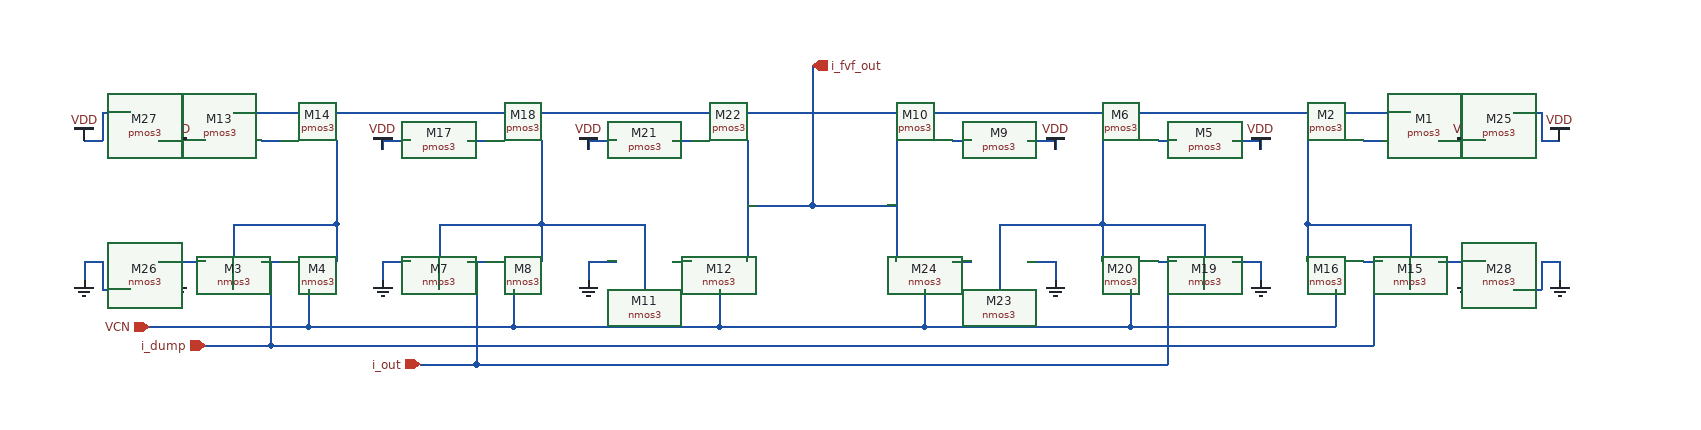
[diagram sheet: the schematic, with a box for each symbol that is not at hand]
v {xschem version=3.4.3 file_version=1.2
}
G {}
K {}
V {}
S {}
E {}
N 770 -210 790 -210 {
lab=#net1}
N -330 -210 -330 -120 {
lab=#net3}
N -410 -80 -390 -80 {
lab=i_dump}
N -440 -120 -330 -120 {
lab=#net3}
N -440 -120 -440 -50 {
lab=#net3}
N -330 -120 -330 -80 {
lab=#net3}
N -360 -50 -360 -10 {
lab=VCN}
N -500 -10 -360 -10 {
lab=VCN}
N -500 -80 -470 -80 {
lab=GND}
N -500 -80 -500 -60 {
lab=GND}
N 880 -210 880 -200 {
lab=VDD}
N 850 -210 880 -210 {
lab=VDD}
N -530 -10 -500 -10 {
lab=VCN}
N 550 -210 570 -210 {
lab=#net4}
N -110 -210 -110 -120 {
lab=#net6}
N -190 -80 -170 -80 {
lab=i_dump}
N -220 -120 -110 -120 {
lab=#net6}
N -220 -120 -220 -50 {
lab=#net6}
N -110 -120 -110 -80 {
lab=#net6}
N -140 -50 -140 -10 {
lab=VCN}
N -280 -10 -140 -10 {
lab=VCN}
N -280 -80 -250 -80 {
lab=GND}
N -280 -80 -280 -60 {
lab=GND}
N 660 -210 660 -200 {
lab=VDD}
N 630 -210 660 -210 {
lab=VDD}
N -310 -10 -280 -10 {
lab=VCN}
N -360 -10 -310 -10 {
lab=VCN}
N -400 -80 -400 10 {
lab=i_dump}
N -470 10 -400 10 {
lab=i_dump}
N -240 30 -180 30 {
lab=i_dump}
N 330 -210 350 -210 {
lab=#net7}
N 110 -210 110 -120 {
lab=i_fvf_out}
N 30 -80 50 -80 {
lab=#net9}
N 0 -120 0 -50 {
lab=#net6}
N 110 -120 110 -80 {
lab=i_fvf_out}
N 80 -50 80 -10 {
lab=VCN}
N -60 -10 80 -10 {
lab=VCN}
N -60 -80 -30 -80 {
lab=GND}
N -60 -80 -60 -60 {
lab=GND}
N 440 -210 440 -200 {
lab=VDD}
N 410 -210 440 -210 {
lab=VDD}
N -90 -10 -60 -10 {
lab=VCN}
N -110 -120 0 -120 {
lab=#net6}
N -140 -10 -90 -10 {
lab=VCN}
N 110 -140 180 -140 {
lab=i_fvf_out}
N -410 -210 -390 -210 {
lab=#net10}
N 710 -210 710 -120 {
lab=#net12}
N 770 -80 790 -80 {
lab=i_dump}
N 710 -120 820 -120 {
lab=#net12}
N 820 -120 820 -50 {
lab=#net12}
N 710 -120 710 -80 {
lab=#net12}
N 740 -50 740 -10 {
lab=VCN}
N 850 -80 880 -80 {
lab=GND}
N 880 -80 880 -60 {
lab=GND}
N -500 -210 -500 -200 {
lab=VDD}
N -500 -210 -470 -210 {
lab=VDD}
N -190 -210 -170 -210 {
lab=#net13}
N 490 -210 490 -120 {
lab=#net15}
N 550 -80 570 -80 {
lab=i_dump}
N 490 -120 600 -120 {
lab=#net15}
N 600 -120 600 -50 {
lab=#net15}
N 490 -120 490 -80 {
lab=#net15}
N 520 -50 520 -10 {
lab=VCN}
N 520 -10 660 -10 {
lab=VCN}
N 630 -80 660 -80 {
lab=GND}
N 660 -80 660 -60 {
lab=GND}
N -280 -210 -280 -200 {
lab=VDD}
N -280 -210 -250 -210 {
lab=VDD}
N 660 -10 690 -10 {
lab=VCN}
N 690 -10 740 -10 {
lab=VCN}
N 30 -210 50 -210 {
lab=#net16}
N 270 -210 270 -120 {
lab=i_fvf_out}
N 330 -80 350 -80 {
lab=#net18}
N 380 -120 380 -50 {
lab=#net15}
N 270 -120 270 -80 {
lab=i_fvf_out}
N 300 -50 300 -10 {
lab=VCN}
N 300 -10 440 -10 {
lab=VCN}
N 410 -80 440 -80 {
lab=GND}
N 440 -80 440 -60 {
lab=GND}
N -60 -210 -60 -200 {
lab=VDD}
N -60 -210 -30 -210 {
lab=VDD}
N 440 -10 470 -10 {
lab=VCN}
N 380 -120 490 -120 {
lab=#net15}
N 470 -10 520 -10 {
lab=VCN}
N 180 -290 180 -140 {
lab=i_fvf_out}
N 180 -140 270 -140 {
lab=i_fvf_out}
N 80 -10 300 -10 {
lab=VCN}
N -180 30 560 30 {
lab=i_dump}
N 560 -80 560 30 {
lab=i_dump}
N -400 10 780 10 {
lab=i_dump}
N 780 -80 780 10 {
lab=i_dump}
N 880 -210 900 -210 {
lab=VDD}
N -520 -80 -500 -80 {
lab=GND}
N -580 -50 -550 -50 {
lab=GND}
N -580 -80 -580 -50 {
lab=GND}
N -600 -80 -580 -80 {
lab=GND}
N 930 -240 960 -240 {
lab=VDD}
N 960 -240 960 -210 {
lab=VDD}
N 960 -210 980 -210 {
lab=VDD}
N -600 -80 -600 -60 {
lab=GND}
N -520 -210 -500 -210 {
lab=VDD}
N 880 -80 900 -80 {
lab=GND}
N 930 -50 960 -50 {
lab=GND}
N 960 -80 960 -50 {
lab=GND}
N 960 -80 980 -80 {
lab=GND}
N -580 -240 -550 -240 {
lab=VDD}
N -580 -240 -580 -210 {
lab=VDD}
N -600 -210 -580 -210 {
lab=VDD}
N 980 -80 980 -60 {
lab=GND}
N -440 -240 820 -240 {}
N -180 -80 -180 30 {}
C {madvlsi/pmos3.sym} 820 -210 1 0 {name=M1
L=4
W=32
body=VDD
nf=1
mult=1
ad="'int((nf+1)/2) * W/nf * 0.29'" 
pd="'2*int((nf+1)/2) * (W/nf + 0.29)'"
as="'int((nf+2)/2) * W/nf * 0.29'" 
ps="'2*int((nf+2)/2) * (W/nf + 0.29)'"
nrd="'0.29 / W'" nrs="'0.29 / W'"
sa=0 sb=0 sd=0
model=pfet_01v8
spiceprefix=X
}
C {madvlsi/pmos3.sym} 740 -210 1 0 {name=M2
L=4
W=32
body=VDD
nf=1
mult=1
ad="'int((nf+1)/2) * W/nf * 0.29'" 
pd="'2*int((nf+1)/2) * (W/nf + 0.29)'"
as="'int((nf+2)/2) * W/nf * 0.29'" 
ps="'2*int((nf+2)/2) * (W/nf + 0.29)'"
nrd="'0.29 / W'" nrs="'0.29 / W'"
sa=0 sb=0 sd=0
model=pfet_01v8
spiceprefix=X
}
C {madvlsi/nmos3.sym} -440 -80 1 1 {name=M3
L=4
W=32
body=GND
nf=1
mult=1
ad="'int((nf+1)/2) * W/nf * 0.29'" 
pd="'2*int((nf+1)/2) * (W/nf + 0.29)'"
as="'int((nf+2)/2) * W/nf * 0.29'" 
ps="'2*int((nf+2)/2) * (W/nf + 0.29)'"
nrd="'0.29 / W'" nrs="'0.29 / W'"
sa=0 sb=0 sd=0
model=nfet_01v8
spiceprefix=X
}
C {madvlsi/nmos3.sym} -360 -80 3 0 {name=M4
L=4
W=32
body=GND
nf=1
mult=1
ad="'int((nf+1)/2) * W/nf * 0.29'" 
pd="'2*int((nf+1)/2) * (W/nf + 0.29)'"
as="'int((nf+2)/2) * W/nf * 0.29'" 
ps="'2*int((nf+2)/2) * (W/nf + 0.29)'"
nrd="'0.29 / W'" nrs="'0.29 / W'"
sa=0 sb=0 sd=0
model=nfet_01v8
spiceprefix=X
}
C {madvlsi/gnd.sym} -500 -60 0 1 {name=l1 lab=GND}
C {madvlsi/vdd.sym} 880 -200 2 0 {name=l2 lab=VDD}
C {madvlsi/pmos3.sym} 600 -210 1 0 {name=M5
L=4
W=32
body=VDD
nf=1
mult=1
ad="'int((nf+1)/2) * W/nf * 0.29'" 
pd="'2*int((nf+1)/2) * (W/nf + 0.29)'"
as="'int((nf+2)/2) * W/nf * 0.29'" 
ps="'2*int((nf+2)/2) * (W/nf + 0.29)'"
nrd="'0.29 / W'" nrs="'0.29 / W'"
sa=0 sb=0 sd=0
model=pfet_01v8
spiceprefix=X
}
C {madvlsi/pmos3.sym} 520 -210 1 0 {name=M6
L=4
W=32
body=VDD
nf=1
mult=1
ad="'int((nf+1)/2) * W/nf * 0.29'" 
pd="'2*int((nf+1)/2) * (W/nf + 0.29)'"
as="'int((nf+2)/2) * W/nf * 0.29'" 
ps="'2*int((nf+2)/2) * (W/nf + 0.29)'"
nrd="'0.29 / W'" nrs="'0.29 / W'"
sa=0 sb=0 sd=0
model=pfet_01v8
spiceprefix=X
}
C {madvlsi/nmos3.sym} -220 -80 1 1 {name=M7
L=4
W=32
body=GND
nf=1
mult=1
ad="'int((nf+1)/2) * W/nf * 0.29'" 
pd="'2*int((nf+1)/2) * (W/nf + 0.29)'"
as="'int((nf+2)/2) * W/nf * 0.29'" 
ps="'2*int((nf+2)/2) * (W/nf + 0.29)'"
nrd="'0.29 / W'" nrs="'0.29 / W'"
sa=0 sb=0 sd=0
model=nfet_01v8
spiceprefix=X
}
C {madvlsi/nmos3.sym} -140 -80 3 0 {name=M8
L=4
W=32
body=GND
nf=1
mult=1
ad="'int((nf+1)/2) * W/nf * 0.29'" 
pd="'2*int((nf+1)/2) * (W/nf + 0.29)'"
as="'int((nf+2)/2) * W/nf * 0.29'" 
ps="'2*int((nf+2)/2) * (W/nf + 0.29)'"
nrd="'0.29 / W'" nrs="'0.29 / W'"
sa=0 sb=0 sd=0
model=nfet_01v8
spiceprefix=X
}
C {madvlsi/gnd.sym} -280 -60 0 1 {name=l3 lab=GND}
C {madvlsi/vdd.sym} 660 -200 2 0 {name=l4 lab=VDD}
C {madvlsi/pmos3.sym} 380 -210 1 0 {name=M9
L=4
W=32
body=VDD
nf=1
mult=1
ad="'int((nf+1)/2) * W/nf * 0.29'" 
pd="'2*int((nf+1)/2) * (W/nf + 0.29)'"
as="'int((nf+2)/2) * W/nf * 0.29'" 
ps="'2*int((nf+2)/2) * (W/nf + 0.29)'"
nrd="'0.29 / W'" nrs="'0.29 / W'"
sa=0 sb=0 sd=0
model=pfet_01v8
spiceprefix=X
}
C {madvlsi/pmos3.sym} 300 -210 1 0 {name=M10
L=4
W=32
body=VDD
nf=1
mult=1
ad="'int((nf+1)/2) * W/nf * 0.29'" 
pd="'2*int((nf+1)/2) * (W/nf + 0.29)'"
as="'int((nf+2)/2) * W/nf * 0.29'" 
ps="'2*int((nf+2)/2) * (W/nf + 0.29)'"
nrd="'0.29 / W'" nrs="'0.29 / W'"
sa=0 sb=0 sd=0
model=pfet_01v8
spiceprefix=X
}
C {madvlsi/nmos3.sym} 0 -80 1 1 {name=M11
L=4
W=32
body=GND
nf=1
mult=1
ad="'int((nf+1)/2) * W/nf * 0.29'" 
pd="'2*int((nf+1)/2) * (W/nf + 0.29)'"
as="'int((nf+2)/2) * W/nf * 0.29'" 
ps="'2*int((nf+2)/2) * (W/nf + 0.29)'"
nrd="'0.29 / W'" nrs="'0.29 / W'"
sa=0 sb=0 sd=0
model=nfet_01v8
spiceprefix=X
}
C {madvlsi/nmos3.sym} 80 -80 3 0 {name=M12
L=4
W=32
body=GND
nf=1
mult=1
ad="'int((nf+1)/2) * W/nf * 0.29'" 
pd="'2*int((nf+1)/2) * (W/nf + 0.29)'"
as="'int((nf+2)/2) * W/nf * 0.29'" 
ps="'2*int((nf+2)/2) * (W/nf + 0.29)'"
nrd="'0.29 / W'" nrs="'0.29 / W'"
sa=0 sb=0 sd=0
model=nfet_01v8
spiceprefix=X
}
C {madvlsi/gnd.sym} -60 -60 0 1 {name=l5 lab=GND}
C {madvlsi/vdd.sym} 440 -200 2 0 {name=l6 lab=VDD}
C {devices/opin.sym} 180 -290 0 0 {name=p6 lab=i_fvf_out}
C {devices/ipin.sym} -470 10 0 0 {name=p7 lab=i_dump}
C {devices/ipin.sym} -240 30 0 0 {name=p8 lab=i_out}
C {devices/ipin.sym} -530 -10 0 0 {name=p9 lab=VCN}
C {madvlsi/pmos3.sym} -440 -210 3 1 {name=M13
L=4
W=32
body=VDD
nf=1
mult=1
ad="'int((nf+1)/2) * W/nf * 0.29'" 
pd="'2*int((nf+1)/2) * (W/nf + 0.29)'"
as="'int((nf+2)/2) * W/nf * 0.29'" 
ps="'2*int((nf+2)/2) * (W/nf + 0.29)'"
nrd="'0.29 / W'" nrs="'0.29 / W'"
sa=0 sb=0 sd=0
model=pfet_01v8
spiceprefix=X
}
C {madvlsi/pmos3.sym} -360 -210 3 1 {name=M14
L=4
W=32
body=VDD
nf=1
mult=1
ad="'int((nf+1)/2) * W/nf * 0.29'" 
pd="'2*int((nf+1)/2) * (W/nf + 0.29)'"
as="'int((nf+2)/2) * W/nf * 0.29'" 
ps="'2*int((nf+2)/2) * (W/nf + 0.29)'"
nrd="'0.29 / W'" nrs="'0.29 / W'"
sa=0 sb=0 sd=0
model=pfet_01v8
spiceprefix=X
}
C {madvlsi/nmos3.sym} 820 -80 3 0 {name=M15
L=4
W=32
body=GND
nf=1
mult=1
ad="'int((nf+1)/2) * W/nf * 0.29'" 
pd="'2*int((nf+1)/2) * (W/nf + 0.29)'"
as="'int((nf+2)/2) * W/nf * 0.29'" 
ps="'2*int((nf+2)/2) * (W/nf + 0.29)'"
nrd="'0.29 / W'" nrs="'0.29 / W'"
sa=0 sb=0 sd=0
model=nfet_01v8
spiceprefix=X
}
C {madvlsi/nmos3.sym} 740 -80 1 1 {name=M16
L=4
W=32
body=GND
nf=1
mult=1
ad="'int((nf+1)/2) * W/nf * 0.29'" 
pd="'2*int((nf+1)/2) * (W/nf + 0.29)'"
as="'int((nf+2)/2) * W/nf * 0.29'" 
ps="'2*int((nf+2)/2) * (W/nf + 0.29)'"
nrd="'0.29 / W'" nrs="'0.29 / W'"
sa=0 sb=0 sd=0
model=nfet_01v8
spiceprefix=X
}
C {madvlsi/gnd.sym} 880 -60 0 0 {name=l7 lab=GND}
C {madvlsi/vdd.sym} -500 -200 2 1 {name=l8 lab=VDD}
C {madvlsi/pmos3.sym} -220 -210 3 1 {name=M17
L=4
W=32
body=VDD
nf=1
mult=1
ad="'int((nf+1)/2) * W/nf * 0.29'" 
pd="'2*int((nf+1)/2) * (W/nf + 0.29)'"
as="'int((nf+2)/2) * W/nf * 0.29'" 
ps="'2*int((nf+2)/2) * (W/nf + 0.29)'"
nrd="'0.29 / W'" nrs="'0.29 / W'"
sa=0 sb=0 sd=0
model=pfet_01v8
spiceprefix=X
}
C {madvlsi/pmos3.sym} -140 -210 3 1 {name=M18
L=4
W=32
body=VDD
nf=1
mult=1
ad="'int((nf+1)/2) * W/nf * 0.29'" 
pd="'2*int((nf+1)/2) * (W/nf + 0.29)'"
as="'int((nf+2)/2) * W/nf * 0.29'" 
ps="'2*int((nf+2)/2) * (W/nf + 0.29)'"
nrd="'0.29 / W'" nrs="'0.29 / W'"
sa=0 sb=0 sd=0
model=pfet_01v8
spiceprefix=X
}
C {madvlsi/nmos3.sym} 600 -80 3 0 {name=M19
L=4
W=32
body=GND
nf=1
mult=1
ad="'int((nf+1)/2) * W/nf * 0.29'" 
pd="'2*int((nf+1)/2) * (W/nf + 0.29)'"
as="'int((nf+2)/2) * W/nf * 0.29'" 
ps="'2*int((nf+2)/2) * (W/nf + 0.29)'"
nrd="'0.29 / W'" nrs="'0.29 / W'"
sa=0 sb=0 sd=0
model=nfet_01v8
spiceprefix=X
}
C {madvlsi/nmos3.sym} 520 -80 1 1 {name=M20
L=4
W=32
body=GND
nf=1
mult=1
ad="'int((nf+1)/2) * W/nf * 0.29'" 
pd="'2*int((nf+1)/2) * (W/nf + 0.29)'"
as="'int((nf+2)/2) * W/nf * 0.29'" 
ps="'2*int((nf+2)/2) * (W/nf + 0.29)'"
nrd="'0.29 / W'" nrs="'0.29 / W'"
sa=0 sb=0 sd=0
model=nfet_01v8
spiceprefix=X
}
C {madvlsi/gnd.sym} 660 -60 0 0 {name=l9 lab=GND}
C {madvlsi/vdd.sym} -280 -200 2 1 {name=l10 lab=VDD}
C {madvlsi/pmos3.sym} 0 -210 3 1 {name=M21
L=4
W=32
body=VDD
nf=1
mult=1
ad="'int((nf+1)/2) * W/nf * 0.29'" 
pd="'2*int((nf+1)/2) * (W/nf + 0.29)'"
as="'int((nf+2)/2) * W/nf * 0.29'" 
ps="'2*int((nf+2)/2) * (W/nf + 0.29)'"
nrd="'0.29 / W'" nrs="'0.29 / W'"
sa=0 sb=0 sd=0
model=pfet_01v8
spiceprefix=X
}
C {madvlsi/pmos3.sym} 80 -210 3 1 {name=M22
L=4
W=32
body=VDD
nf=1
mult=1
ad="'int((nf+1)/2) * W/nf * 0.29'" 
pd="'2*int((nf+1)/2) * (W/nf + 0.29)'"
as="'int((nf+2)/2) * W/nf * 0.29'" 
ps="'2*int((nf+2)/2) * (W/nf + 0.29)'"
nrd="'0.29 / W'" nrs="'0.29 / W'"
sa=0 sb=0 sd=0
model=pfet_01v8
spiceprefix=X
}
C {madvlsi/nmos3.sym} 380 -80 3 0 {name=M23
L=4
W=32
body=GND
nf=1
mult=1
ad="'int((nf+1)/2) * W/nf * 0.29'" 
pd="'2*int((nf+1)/2) * (W/nf + 0.29)'"
as="'int((nf+2)/2) * W/nf * 0.29'" 
ps="'2*int((nf+2)/2) * (W/nf + 0.29)'"
nrd="'0.29 / W'" nrs="'0.29 / W'"
sa=0 sb=0 sd=0
model=nfet_01v8
spiceprefix=X
}
C {madvlsi/nmos3.sym} 300 -80 1 1 {name=M24
L=4
W=32
body=GND
nf=1
mult=1
ad="'int((nf+1)/2) * W/nf * 0.29'" 
pd="'2*int((nf+1)/2) * (W/nf + 0.29)'"
as="'int((nf+2)/2) * W/nf * 0.29'" 
ps="'2*int((nf+2)/2) * (W/nf + 0.29)'"
nrd="'0.29 / W'" nrs="'0.29 / W'"
sa=0 sb=0 sd=0
model=nfet_01v8
spiceprefix=X
}
C {madvlsi/gnd.sym} 440 -60 0 0 {name=l11 lab=GND}
C {madvlsi/vdd.sym} -60 -200 2 1 {name=l12 lab=VDD}
C {madvlsi/pmos3.sym} 930 -210 1 0 {name=M25
L=4
W=32
body=VDD
nf=1
mult=1
ad="'int((nf+1)/2) * W/nf * 0.29'" 
pd="'2*int((nf+1)/2) * (W/nf + 0.29)'"
as="'int((nf+2)/2) * W/nf * 0.29'" 
ps="'2*int((nf+2)/2) * (W/nf + 0.29)'"
nrd="'0.29 / W'" nrs="'0.29 / W'"
sa=0 sb=0 sd=0
model=pfet_01v8
spiceprefix=X
}
C {madvlsi/nmos3.sym} -550 -80 1 1 {name=M26
L=4
W=32
body=GND
nf=1
mult=1
ad="'int((nf+1)/2) * W/nf * 0.29'" 
pd="'2*int((nf+1)/2) * (W/nf + 0.29)'"
as="'int((nf+2)/2) * W/nf * 0.29'" 
ps="'2*int((nf+2)/2) * (W/nf + 0.29)'"
nrd="'0.29 / W'" nrs="'0.29 / W'"
sa=0 sb=0 sd=0
model=nfet_01v8
spiceprefix=X
}
C {madvlsi/vdd.sym} 980 -210 2 0 {name=l13 lab=VDD}
C {madvlsi/gnd.sym} -600 -60 0 1 {name=l14 lab=GND}
C {madvlsi/pmos3.sym} -550 -210 3 1 {name=M27
L=4
W=32
body=VDD
nf=1
mult=1
ad="'int((nf+1)/2) * W/nf * 0.29'" 
pd="'2*int((nf+1)/2) * (W/nf + 0.29)'"
as="'int((nf+2)/2) * W/nf * 0.29'" 
ps="'2*int((nf+2)/2) * (W/nf + 0.29)'"
nrd="'0.29 / W'" nrs="'0.29 / W'"
sa=0 sb=0 sd=0
model=pfet_01v8
spiceprefix=X
}
C {madvlsi/nmos3.sym} 930 -80 3 0 {name=M28
L=4
W=32
body=GND
nf=1
mult=1
ad="'int((nf+1)/2) * W/nf * 0.29'" 
pd="'2*int((nf+1)/2) * (W/nf + 0.29)'"
as="'int((nf+2)/2) * W/nf * 0.29'" 
ps="'2*int((nf+2)/2) * (W/nf + 0.29)'"
nrd="'0.29 / W'" nrs="'0.29 / W'"
sa=0 sb=0 sd=0
model=nfet_01v8
spiceprefix=X
}
C {madvlsi/vdd.sym} -600 -210 2 1 {name=l15 lab=VDD}
C {madvlsi/gnd.sym} 980 -60 0 0 {name=l16 lab=GND}
